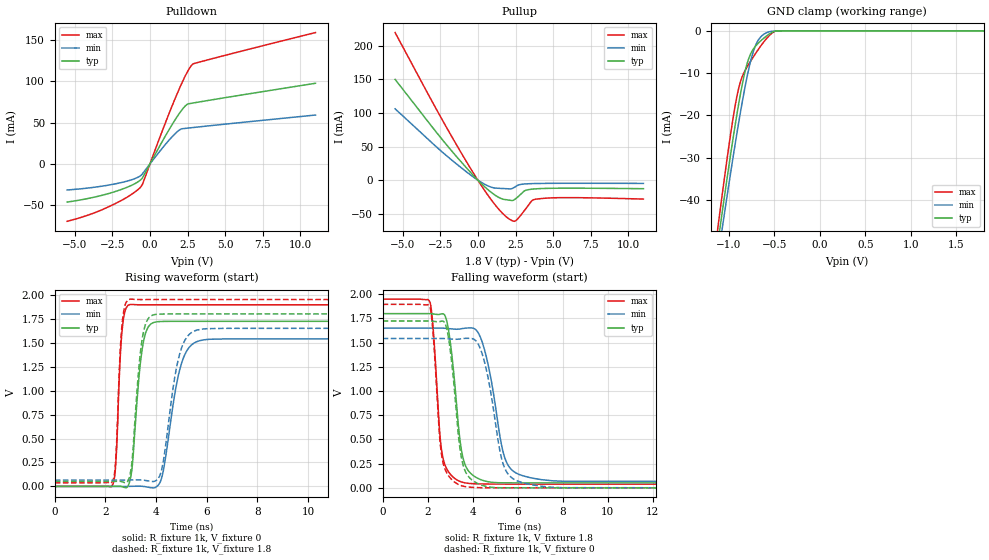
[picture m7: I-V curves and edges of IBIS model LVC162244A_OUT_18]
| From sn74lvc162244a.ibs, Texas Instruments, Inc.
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[Model]   LVC162244A_OUT_18
Model_type  3-state
Enable   Active-Low
Vref =   0
Rref =   1000
Cref =   30p
Vmeas =   0.9
| variable   typ   min   max
C_comp   4.47pF   3.89pF   5.46pF
| C_pullup   3.84pF   2.69pF   5.54pF
| C_pulldown   2.93pF   2.58pF   3.62pF
| C_tri-state   4.47pF   3.89pF   5.46pF
[Temperature Range]   40   100   -40
| Ambient temperature   25   85   -40
[Voltage range]   1.8   1.65   1.95
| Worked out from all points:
|   slope of the pulldown table from 0 to 0.27 V, typ, clamps not added: 29.5 ohm
|   slope of the pullup table from 0 to 0.27 V, typ, clamps not added: 45.1 ohm
|   GND clamp passes 1 mA (typ) near -0.57 V on its own axis
|   rising waveform, R_fixture 1k, V_fixture 0: 20-80 % time 321ps typ, 571ps min, 185ps max; typ from 0 V to 1.72 V
|   falling waveform, R_fixture 1k, V_fixture 1.8: 20-80 % time 458ps typ, 713ps min, 331ps max; typ from 1.8 V to 0.051 V
|   rising waveform, R_fixture 1k, V_fixture 1.8: 20-80 % time 312ps typ, 530ps min, 183ps max; typ from 0.051 V to 1.8 V
|   falling waveform, R_fixture 1k, V_fixture 0: 20-80 % time 449ps typ, 685ps min, 329ps max; typ from 1.72 V to 0 V
[GND Clamp]
| LVC162244A_OUT_18
|   Voltage   I(typ)   I(min)   I(max)
-5.5V     -793.1mA   -760.6mA   -846.1mA
-1.115V   -49.39mA   -52.98mA   -45.67mA
-1.09V    -45.55mA   -49.31mA   -41.57mA
-1.065V   -41.75mA   -45.67mA   -37.51mA
-950mV    -24.99mA   -29.45mA   -20.23mA
-880mV    -15.86mA   -20.24mA   -12.61mA
-810mV    -8.614mA   -12mA      -8.944mA
-740mV    -4.623mA   -5.564mA   -6.472mA
-690mV    -3.222mA   -2.714mA   -4.837mA
-620mV    -1.813mA   -880.7uA   -2.743mA
-475mV    -25.37uA   -59.7uA    -23.68uA
1.8V      55.43pA    12.38nA    -7.727nA
[Pulldown]
| LVC162244A_OUT_18
|   Voltage   I(typ)   I(min)   I(max)
-5.5V     -46.21mA   -31.58mA   -69.55mA
-3.97V    -41.35mA   -28.91mA   -61.15mA
-2.635V   -35.31mA   -25.31mA   -51mA
-1.415V   -27.52mA   -20.29mA   -39.15mA
-605mV    -19.04mA   -13.97mA   -27.74mA
-480mV    -16.31mA   -11.45mA   -23.84mA
815mV     27.14mA    18.99mA    39.81mA
1.755V    55.86mA    38.1mA     82.82mA
2.065V    64.07mA    42.27mA    95.81mA
2.395V    71.09mA    43.16mA    108.4mA
2.85V     73.79mA    44.08mA    121mA
11V       97.75mA    59.27mA    159.2mA
[Pullup]
| LVC162244A_OUT_18
|   Voltage   I(typ)   I(min)   I(max)
-5.5V     149.9mA    106.1mA    219.6mA
-2.305V   58.69mA    40.64mA    87.23mA
-170mV    3.94mA     2.589mA    6.028mA
585mV     -12.48mA   -7.588mA   -19.72mA
1.15V     -22.4mA    -11.77mA   -36.79mA
2.075V    -29.65mA   -12.86mA   -57.67mA
2.525V    -27.28mA   -9.296mA   -60.1mA
3.115V    -15.67mA   -5.629mA   -44.5mA
3.575V    -13.41mA   -5.126mA   -30.83mA
3.87V     -12.84mA   -4.957mA   -28.2mA
5.955V    -11.89mA   -4.61mA    -25.94mA
11V       -12.66mA   -4.792mA   -28.08mA
[Ramp]
| LVC162244A_OUT_18
| variable   typ   min   max
dV/dt_r   1.04/3.32E-10   0.93/5.77E-10   1.14/1.90E-10
dV/dt_f   1.05/4.66E-10   0.95/7.17E-10   1.15/3.40E-10
R_load = 1k
[Rising Waveform]
| LVC162244A_OUT_18
R_fixture =   1k
C_fixture =   0
L_fixture =   0
V_fixture =   0
V_fixture_min = 0
V_fixture_max = 0
|   Time   V(typ)   V(min)   V(max)
0s        512.1pV    2.021nV    70.27nV
2.305ns   391.6uV    -40.69uV   29.1mV
2.65ns    -1.723mV   -151.6uV   1.609V
2.97ns    64.75mV    959.6uV    1.898V
3.45ns    1.433V     1.471mV    1.895V
3.915ns   1.712V     -14.91mV   1.895V
4.26ns    1.722V     132.8mV    1.896V
5ns       1.723V     1.283V     1.896V
5.71ns    1.723V     1.52V      1.896V
24.99ns   1.723V     1.54V      1.896V
[Falling Waveform]
| LVC162244A_OUT_18
R_fixture =   1k
C_fixture =   0
L_fixture =   0
V_fixture =   1.8
V_fixture_min = 1.65
V_fixture_max = 1.95
|   Time   V(typ)   V(min)   V(max)
0s        1.8V       1.65V      1.95V
2.11ns    1.8V       1.65V      1.915V
2.25ns    1.796V     1.65V      1.626V
2.635ns   1.799V     1.65V      365.2mV
2.975ns   1.556V     1.644V     150.2mV
3.495ns   396.6mV    1.644V     61.5mV
4.345ns   86.36mV    1.555V     40.52mV
5.4ns     52.3mV     329.9mV    38.88mV
6.23ns    51.6mV     124.6mV    38.69mV
24.99ns   51.4mV     66.1mV     38.41mV
[Rising Waveform]
| LVC162244A_OUT_18
R_fixture =   1k
C_fixture =   0
L_fixture =   0
V_fixture =   1.8
V_fixture_min = 1.65
V_fixture_max = 1.95
|   Time   V(typ)   V(min)   V(max)
0s        51.33mV    66.07mV    38.4mV
2.305ns   51.72mV    66.03mV    68.42mV
2.64ns    50.04mV    65.94mV    1.646V
2.915ns   71.81mV    66.69mV    1.95V
3.44ns    1.52V      67.22mV    1.95V
3.895ns   1.79V      51.36mV    1.95V
4.25ns    1.799V     213.2mV    1.95V
4.935ns   1.8V       1.388V     1.95V
5.61ns    1.8V       1.631V     1.95V
24.99ns   1.8V       1.65V      1.95V
[Falling Waveform]
| LVC162244A_OUT_18
R_fixture =   1k
C_fixture =   0
L_fixture =   0
V_fixture =   0
V_fixture_min = 0
V_fixture_max = 0
|   Time   V(typ)   V(min)   V(max)
0s        1.724V     1.543V     1.896V
2.11ns    1.723V     1.543V     1.861V
2.245ns   1.721V     1.543V     1.583V
2.63ns    1.723V     1.544V     323.8mV
2.965ns   1.488V     1.538V     112.9mV
3.495ns   316.7mV    1.541V     22.69mV
4.325ns   34.93mV    1.446V     2.179mV
5.335ns   1.039mV    260.7mV    508.5uV
6.17ns    273.2uV    56.47mV    294.6uV
24.99ns   66.81uV    35.84uV    18.32uV
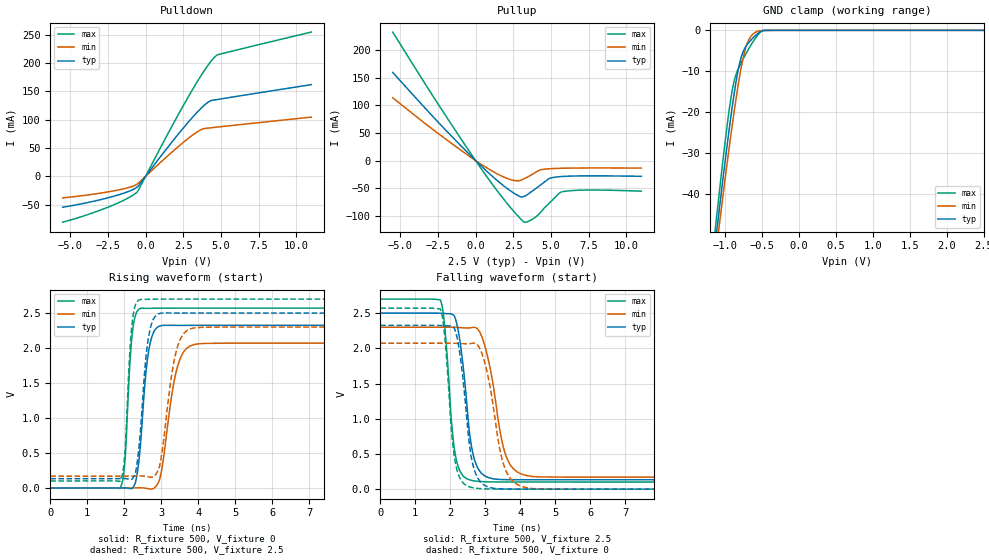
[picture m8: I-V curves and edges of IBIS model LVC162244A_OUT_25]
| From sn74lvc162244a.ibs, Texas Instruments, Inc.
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[Model]   LVC162244A_OUT_25
Model_type  3-state
Enable   Active-Low
Vref =   0
Rref =   500
Cref =   30p
Vmeas =   1.25
| variable   typ   min   max
C_comp   4.28pF   3.65pF   5.41pF
| C_pullup   3.16pF   2.37pF   4.89pF
| C_pulldown   2.67pF   2.25pF   3.58pF
| C_tri-state   4.28pF   3.65pF   5.41pF
[Temperature Range]   40   100   -40
| Ambient temperature   25   85   -40
[Voltage range]   2.5   2.3   2.7
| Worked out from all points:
|   slope of the pulldown table from 0 to 0.375 V, typ, clamps not added: 28.3 ohm
|   slope of the pullup table from 0 to 0.375 V, typ, clamps not added: 37.8 ohm
|   GND clamp passes 1 mA (typ) near -0.57 V on its own axis
|   rising waveform, R_fixture 500, V_fixture 0: 20-80 % time 222ps typ, 343ps min, 154ps max; typ from 0 V to 2.32 V
|   falling waveform, R_fixture 500, V_fixture 2.5: 20-80 % time 310ps typ, 447ps min, 239ps max; typ from 2.5 V to 0.134 V
|   rising waveform, R_fixture 500, V_fixture 2.5: 20-80 % time 218ps typ, 327ps min, 149ps max; typ from 0.133 V to 2.5 V
|   falling waveform, R_fixture 500, V_fixture 0: 20-80 % time 307ps typ, 434ps min, 240ps max; typ from 2.33 V to 0 V
[GND Clamp]
| LVC162244A_OUT_25
|   Voltage   I(typ)   I(min)   I(max)
-5.5V     -793.1mA   -760.6mA   -846.1mA
-1.145V   -54.03mA   -57.41mA   -50.66mA
-1.12V    -50.16mA   -53.71mA   -46.5mA
-1.095V   -46.31mA   -50.04mA   -42.38mA
-1.07V    -42.51mA   -46.39mA   -38.32mA
-960mV    -26.39mA   -30.82mA   -21.59mA
-885mV    -16.47mA   -20.88mA   -13.01mA
-815mV    -9.034mA   -12.54mA   -9.137mA
-745mV    -4.806mA   -5.936mA   -6.641mA
-610mV    -1.634mA   -735.6uA   -2.468mA
-475mV    -25.37uA   -59.7uA    -23.69uA
2.5V      69.81pA    32.24nA    -8.366nA
[Pulldown]
| LVC162244A_OUT_25
|   Voltage   I(typ)   I(min)   I(max)
-5.5V     -54.71mA   -38.13mA   -81.1mA
-3.945V   -46.96mA   -33.31mA   -68.65mA
-2.365V   -37.06mA   -26.95mA   -53.19mA
-1.26V    -28.05mA   -20.82mA   -39.75mA
-565mV    -19.14mA   -13.96mA   -27.83mA
1.78V     61.6mA     43.45mA    90mA
3.185V    106.3mA    74.07mA    156.4mA
3.735V    121.6mA    83.09mA    180.2mA
4.12V     130.5mA    85.13mA    195.5mA
4.35V     133.9mA    85.81mA    203.6mA
4.695V    135.5mA    86.82mA    213.3mA
11V       162mA      104.6mA    254.9mA
[Pullup]
| LVC162244A_OUT_25
|   Voltage   I(typ)   I(min)   I(max)
-5.5V     159.3mA    113.5mA    232.3mA
-2.51V    70.18mA    49.49mA    103.1mA
715mV     -18.63mA   -12.68mA   -27.98mA
2.305V    -54.59mA   -34.37mA   -84.62mA
2.98V     -65.7mA    -35.85mA   -105.1mA
3.195V    -65.06mA   -33.35mA   -110.9mA
3.92V     -52.21mA   -22.37mA   -103.5mA
4.28V     -44.92mA   -17.12mA   -94.73mA
4.855V    -32.95mA   -14.93mA   -78.07mA
5.75V     -28.83mA   -13.92mA   -56.48mA
7.48V     -27.68mA   -13.45mA   -53.33mA
11V       -28.5mA    -13.65mA   -55.36mA
[Ramp]
| LVC162244A_OUT_25
| variable   typ   min   max
dV/dt_r   1.40/2.28E-10   1.25/3.52E-10   1.55/1.58E-10
dV/dt_f   1.42/3.14E-10   1.28/4.53E-10   1.56/2.47E-10
R_load = 500
[Rising Waveform]
| LVC162244A_OUT_25
R_fixture =   500
C_fixture =   0
L_fixture =   0
V_fixture =   0
V_fixture_min = 0
V_fixture_max = 0
|   Time   V(typ)   V(min)   V(max)
0s        556.3pV    1.722nV    63.86nV
1.9ns     881.8uV    -49.16uV   8.984mV
2.025ns   2.264mV    -36.43uV   410.2mV
2.22ns    -3.077mV   683uV      2.213V
2.465ns   785.3mV    2.427mV    2.569V
2.625ns   1.819V     -7.497mV   2.568V
2.805ns   2.236V     -2.824mV   2.569V
3.45ns    2.324V     1.748V     2.571V
3.93ns    2.324V     2.054V     2.571V
24.99ns   2.324V     2.07V      2.571V
[Falling Waveform]
| LVC162244A_OUT_25
R_fixture =   500
C_fixture =   0
L_fixture =   0
V_fixture =   2.5
V_fixture_min = 2.3
V_fixture_max = 2.7
|   Time   V(typ)   V(min)   V(max)
0s        2.5V       2.3V       2.7V
1.72ns    2.499V     2.3V       2.688V
1.84ns    2.495V     2.3V       2.321V
2.14ns    2.431V     2.299V     507mV
2.32ns    1.951V     2.293V     221.2mV
2.635ns   539.9mV    2.297V     122.3mV
3.02ns    180.5mV    1.98V      105mV
3.6ns     135.3mV    465.4mV    101.9mV
4.215ns   133.8mV    189.5mV    101.3mV
24.99ns   133.5mV    169.7mV    100.6mV
[Rising Waveform]
| LVC162244A_OUT_25
R_fixture =   500
C_fixture =   0
L_fixture =   0
V_fixture =   2.5
V_fixture_min = 2.3
V_fixture_max = 2.7
|   Time   V(typ)   V(min)   V(max)
0s        133.5mV    169.7mV    100.6mV
1.9ns     134.3mV    169.7mV    110.2mV
2.02ns    135.8mV    169.7mV    506.3mV
2.21ns    125.8mV    170.3mV    2.333V
2.43ns    754.7mV    172.5mV    2.693V
2.605ns   1.948V     163.4mV    2.697V
2.785ns   2.407V     162mV      2.699V
3.42ns    2.5V       1.978V     2.7V
3.89ns    2.5V       2.287V     2.7V
24.99ns   2.5V       2.3V       2.7V
[Falling Waveform]
| LVC162244A_OUT_25
R_fixture =   500
C_fixture =   0
L_fixture =   0
V_fixture =   0
V_fixture_min = 0
V_fixture_max = 0
|   Time   V(typ)   V(min)   V(max)
0s        2.326V     2.073V     2.571V
1.72ns    2.325V     2.073V     2.559V
1.835ns   2.322V     2.073V     2.213V
2.14ns    2.255V     2.072V     392.2mV
2.3ns     1.835V     2.068V     134.4mV
2.635ns   378.2mV    2.073V     21.46mV
3ns       49.41mV    1.774V     4.554mV
3.57ns    1.859mV    290.2mV    1.369mV
4.2ns     361.4uV    18.82mV    702.9uV
24.99ns   62.87uV    22.08uV    15.51uV
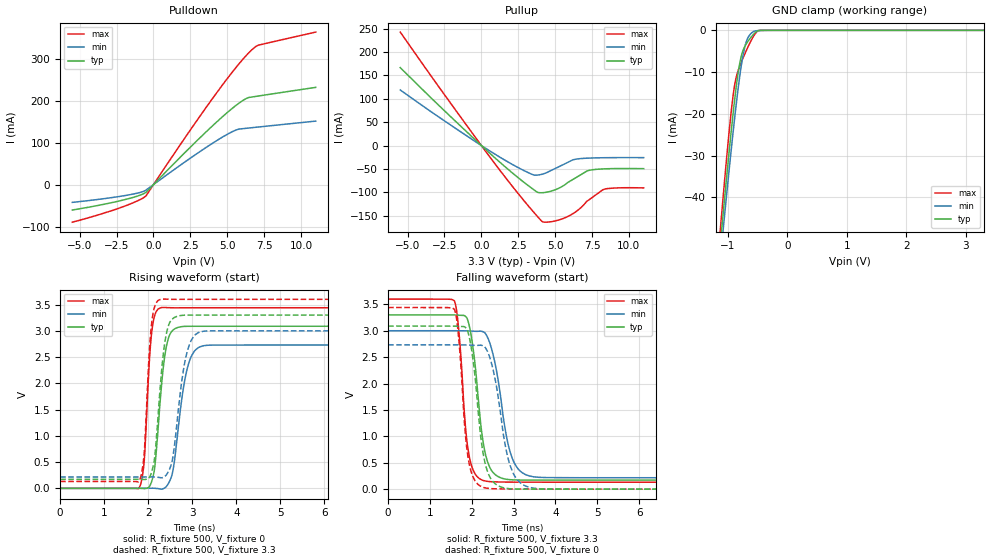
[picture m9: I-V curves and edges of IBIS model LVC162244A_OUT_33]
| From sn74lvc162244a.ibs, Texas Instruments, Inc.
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[Model]   LVC162244A_OUT_33
Model_type  3-state
Enable   Active-Low
Vref =   0
Rref =   500
Cref =   50p
Vmeas =   1.5
| variable   typ   min   max
C_comp   4.11pF   3.46pF   5.38pF
| C_pullup   2.82pF   2.15pF   4.23pF
| C_pulldown   2.53pF   2.05pF   3.59pF
| C_tri-state   4.11pF   3.46pF   5.38pF
[Temperature Range]   40   100   -40
| Ambient temperature   25   85   -40
[Voltage range]   3.3   3   3.6
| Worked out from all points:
|   slope of the pulldown table from 0 to 0.495 V, typ, clamps not added: 27.6 ohm
|   slope of the pullup table from 0 to 0.495 V, typ, clamps not added: 34.5 ohm
|   GND clamp passes 1 mA (typ) near -0.57 V on its own axis
|   rising waveform, R_fixture 500, V_fixture 0: 20-80 % time 194ps typ, 260ps min, 132ps max; typ from 0 V to 3.09 V
|   falling waveform, R_fixture 500, V_fixture 3.3: 20-80 % time 262ps typ, 353ps min, 196ps max; typ from 3.3 V to 0.172 V
|   rising waveform, R_fixture 500, V_fixture 3.3: 20-80 % time 190ps typ, 251ps min, 130ps max; typ from 0.172 V to 3.3 V
|   falling waveform, R_fixture 500, V_fixture 0: 20-80 % time 259ps typ, 349ps min, 195ps max; typ from 3.09 V to 0 V
[GND Clamp]
| LVC162244A_OUT_33
|   Voltage   I(typ)   I(min)   I(max)
-5.5V     -793.1mA   -760.6mA   -846.1mA
-1.125V   -50.93mA   -54.45mA   -47.33mA
-1.1V     -47.08mA   -50.77mA   -43.2mA
-1.075V   -43.26mA   -47.12mA   -39.13mA
-925mV    -21.59mA   -26.08mA   -17.08mA
-875mV    -15.26mA   -19.62mA   -12.24mA
-820mV    -9.472mA   -13.09mA   -9.334mA
-770mV    -5.925mA   -8.019mA   -7.498mA
-715mV    -3.846mA   -3.939mA   -5.643mA
-585mV    -1.209mA   -444.3uA   -1.816mA
-445mV    -10.5uA    -38.5uA    -12uA
3.3V      86.23pA    54.92nA    -8.992nA
[Pulldown]
| LVC162244A_OUT_33
|   Voltage   I(typ)   I(min)   I(max)
-5.5V     -60.56mA   -42.31mA   -89.53mA
-2.25V    -38.36mA   -27.9mA    -55.06mA
-1.17V    -28.24mA   -20.97mA   -40.05mA
-540mV    -19.1mA    -13.8mA    -27.79mA
2.65V     94.37mA    66.67mA    137.8mA
4.82V     166.1mA    116.1mA    244mA
5.615V    189.3mA    130.2mA    279.9mA
6.12V     201.7mA    133.6mA    301mA
6.45V     207.4mA    134.8mA    313.6mA
6.855V    209.7mA    136.3mA    326.7mA
7.15V     211.3mA    137.4mA    332.7mA
11V       231.7mA    151.3mA    363.4mA
[Pullup]
| LVC162244A_OUT_33
|   Voltage   I(typ)   I(min)   I(max)
-5.5V     166.8mA    119mA      242.8mA
-1.93V    57.22mA    40.57mA    83.77mA
1.475V    -41.86mA   -29.08mA   -62.05mA
3.51V     -93.62mA   -62.61mA   -141.4mA
3.815V    -100.2mA   -63.23mA   -152.4mA
4.115V    -101mA     -61.38mA   -162.5mA
5.085V    -93.67mA   -47.95mA   -160.8mA
5.945V    -77.42mA   -34.62mA   -150.5mA
6.59V     -65.36mA   -28.4mA    -137.2mA
7.195V    -54.16mA   -27.03mA   -118.5mA
8.315V    -49.95mA   -26.1mA    -93.66mA
11V       -49.52mA   -25.91mA   -90.73mA
[Ramp]
| LVC162244A_OUT_33
| variable   typ   min   max
dV/dt_r   1.85/2.00E-10   1.65/2.69E-10   2.07/1.35E-10
dV/dt_f   1.88/2.66E-10   1.67/3.60E-10   2.08/2.02E-10
R_load = 500
[Rising Waveform]
| LVC162244A_OUT_33
R_fixture =   500
C_fixture =   0
L_fixture =   0
V_fixture =   0
V_fixture_min = 0
V_fixture_max = 0
|   Time   V(typ)   V(min)   V(max)
0s        628pV      1.653nV    62.78nV
1.8ns     1.725mV    35.04uV    21.33mV
1.905ns   -3.192mV   436.5uV    479.3mV
2.085ns   150.3mV    2.527mV    3.014V
2.165ns   541mV      15.49uV    3.338V
2.305ns   1.992V     -15.45mV   3.443V
2.52ns    2.973V     203.9mV    3.44V
2.88ns    3.086V     2.26V      3.439V
3.265ns   3.087V     2.718V     3.44V
24.99ns   3.087V     2.73V      3.44V
[Falling Waveform]
| LVC162244A_OUT_33
R_fixture =   500
C_fixture =   0
L_fixture =   0
V_fixture =   3.3
V_fixture_min = 3
V_fixture_max = 3.6
|   Time   V(typ)   V(min)   V(max)
0s        3.3V       3V         3.6V
1.585ns   3.299V     3V         3.567V
1.69ns    3.295V     3V         3.01V
1.84ns    3.278V     2.998V     1.278V
1.935ns   3.115V     2.996V     642.1mV
2.355ns   580mV      2.912V     149.9mV
2.565ns   273.4mV    2.352V     138.1mV
2.935ns   178.7mV    661.1mV    133.6mV
3.48ns    172.5mV    233.7mV    132.2mV
24.99ns   172.1mV    216.1mV    131mV
[Rising Waveform]
| LVC162244A_OUT_33
R_fixture =   500
C_fixture =   0
L_fixture =   0
V_fixture =   3.3
V_fixture_min = 3
V_fixture_max = 3.6
|   Time   V(typ)   V(min)   V(max)
0s        172mV      216.1mV    131mV
1.795ns   173.6mV    216.1mV    145.5mV
1.905ns   168.6mV    216.5mV    631.9mV
2.08ns    317mV      218.5mV    3.161V
2.16ns    707.7mV    216.1mV    3.497V
2.3ns     2.202V     200.8mV    3.604V
2.51ns    3.189V     420.7mV    3.6V
2.865ns   3.299V     2.538V     3.6V
3.25ns    3.3V       2.992V     3.6V
24.99ns   3.3V       3V         3.6V
[Falling Waveform]
| LVC162244A_OUT_33
R_fixture =   500
C_fixture =   0
L_fixture =   0
V_fixture =   0
V_fixture_min = 0
V_fixture_max = 0
|   Time   V(typ)   V(min)   V(max)
0s        3.088V     2.732V     3.44V
1.585ns   3.087V     2.732V     3.407V
1.685ns   3.084V     2.732V     2.887V
1.835ns   3.07V      2.731V     1.156V
1.93ns    2.917V     2.729V     520.4mV
2.355ns   388.5mV    2.642V     19.07mV
2.55ns    109.5mV    2.118V     7.339mV
2.92ns    7.666mV    443.1mV    2.693mV
3.48ns    497.6uV    18.1mV     1.24mV
24.99ns   78.66uV    14.07uV    16uV
